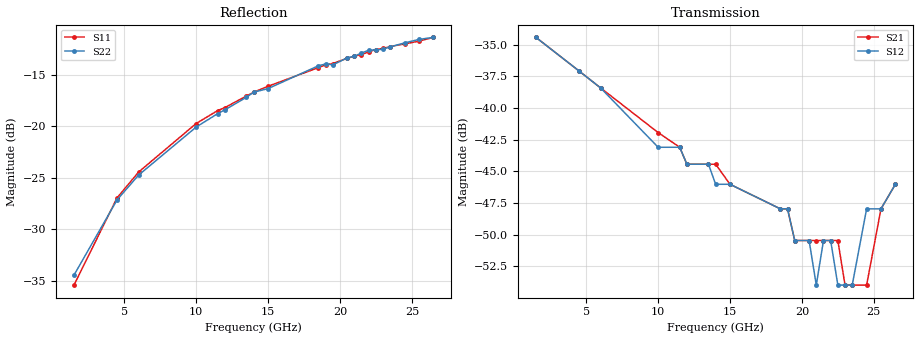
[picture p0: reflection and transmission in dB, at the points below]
! HMMC-1002
! S-PARAMETERS at  Maximum Attenuation;  V1 = -4V;  V2 = 0V.  LAST UPDATED 07/06/99
# GHZ  S  MA  R  50
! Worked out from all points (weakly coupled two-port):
!   51 points, 1.5 GHz to 26.5 GHz, reference 50 ohm
!   highest |S21| = -34.42 dB at 1.5 GHz (marker M1); lowest = -54.0 dB at 23 GHz (marker M2)
!   lowest |S11| = -35.4 dB at 1.5 GHz (marker M3), VSWR 1.03, Z = 51.2 - j1.23 ohm
!   |S11| at or under -10 dB: start of sweep to end of sweep
!   |S22| runs from -34.4 to -11.4 dB; largest |S21 - S12| = 0.0021
!   S11 on the Smith chart (normalised r, x): 1.5 GHz: 1.02, -0.02; 15 GHz: 0.74, -0.08; 26.5 GHz: 0.67, +0.32
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1.5  0.017 -45.0  0.019 -20.6  0.019 -21.3  0.019 -41.0
4.5  0.045 -83.6  0.014 -53.7  0.014 -53.3  0.044 -81.0
6  0.06 -97.8  0.012 -63.1  0.012 -63.2  0.058 -97.1
10  0.103 -127.7  0.008 -74.3  0.007 -76.9  0.099 -128.7
11.5  0.119 -138.0  0.007 -80.3  0.007 -80.0  0.115 -138.7
12  0.123 -141.4  0.006 -80.4  0.006 -79.8  0.12 -142.5
13.5  0.14 -151.0  0.006 -82.0  0.006 -81.6  0.138 -154.8
14  0.146 -154.0  0.006 -86.0  0.005 -83.9  0.146 -157.2
15  0.156 -160.5  0.005 -86.2  0.005 -89.1  0.152 -162.6
18.5  0.192 177.0  0.004 -94.5  0.004 -94.1  0.196 175.6
19  0.198 174.0  0.004 -90.7  0.004 -93.1  0.2 170.9
19.5  0.201 170.1  0.003 -92.4  0.003 -92.8  0.198 167.6
20.5  0.213 164.2  0.003 -94.4  0.003 -96.6  0.214 159.6
21  0.218 160.4  0.003 -76.6  0.002 -88.2  0.218 156.6
21.5  0.222 157.7  0.003 -84.7  0.003 -80.2  0.226 155.1
22  0.229 154.7  0.003 -88.4  0.003 -86.0  0.233 152.2
22.5  0.235 150.9  0.003 -74.6  0.002 -91.7  0.234 149.2
23  0.238 147.7  0.002 -82.1  0.002 -81.0  0.236 146.5
23.5  0.243 144.2  0.002 -59.2  0.002 -61.0  0.242 142.4
24.5  0.25 137.0  0.002 -41.3  0.004 -54.3  0.253 133.8
25.5  0.258 129.9  0.004 -46.2  0.004 -39.3  0.263 127.7
26.5  0.269 124.3  0.005 -53.2  0.005 -63.3  0.269 123.0
